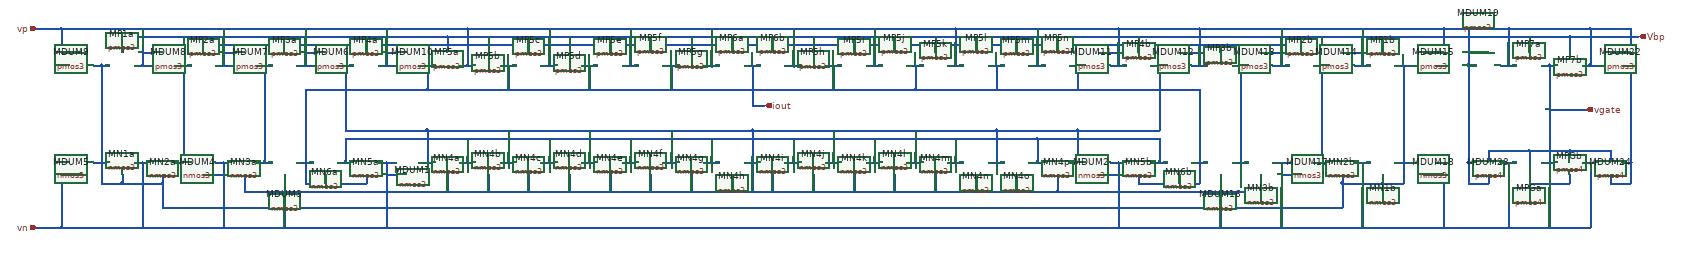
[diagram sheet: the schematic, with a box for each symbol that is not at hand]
v {xschem version=2.9.9 file_version=1.2 }
G {}
K {}
V {}
S {}
E {}
N 4100 -430 4250 -430 { lab=vp}
N 4360 -230 4450 -230 { lab=igate}
N 1680 -340 1700 -340 { lab=vp}
N 900 -340 920 -340 { lab=vp}
N 1080 -340 1120 -340 { lab=vp}
N 1100 -430 1100 -340 { lab=vp}
N 1480 -340 1520 -340 { lab=vp}
N 1280 -340 1320 -340 { lab=vp}
N 980 -340 1020 -340 { lab=Vbp}
N 1380 -340 1420 -340 { lab=#net1}
N 1580 -340 1620 -340 { lab=#net2}
N 950 -410 1050 -410 { lab=Vbp}
N 1650 -410 1650 -370 { lab=Vbp}
N 1650 -410 1830 -410 { lab=Vbp}
N 870 -430 910 -430 { lab=vp}
N 910 -430 1680 -430 { lab=vp}
N 1680 -430 1700 -430 { lab=vp}
N 1100 -100 1120 -100 { lab=vn}
N 1830 -410 2920 -410 { lab=Vbp}
N 1700 -340 1720 -340 { lab=vp}
N 1700 -430 2900 -430 { lab=vp}
N 1780 -340 1820 -340 { lab=#net2}
N 1880 -340 1920 -340 { lab=vp}
N 1980 -340 2020 -340 { lab=#net2}
N 2080 -340 2120 -340 { lab=vp}
N 2180 -340 2220 -340 { lab=#net2}
N 2280 -340 2320 -340 { lab=vp}
N 2380 -340 2420 -340 { lab=iout}
N 2480 -340 2520 -340 { lab=vp}
N 2580 -340 2620 -340 { lab=#net2}
N 2680 -340 2720 -340 { lab=vp}
N 2780 -340 2820 -340 { lab=#net2}
N 1850 -410 1850 -370 { lab=Vbp}
N 1750 -410 1750 -370 { lab=Vbp}
N 2050 -410 2050 -370 { lab=Vbp}
N 1950 -410 1950 -370 { lab=Vbp}
N 2250 -410 2250 -370 { lab=Vbp}
N 2150 -410 2150 -370 { lab=Vbp}
N 2450 -410 2450 -370 { lab=Vbp}
N 2350 -410 2350 -370 { lab=Vbp}
N 2650 -410 2650 -370 { lab=Vbp}
N 2550 -410 2550 -370 { lab=Vbp}
N 2850 -410 2850 -370 { lab=Vbp}
N 2750 -410 2750 -370 { lab=Vbp}
N 1600 -280 2800 -280 { lab=#net2}
N 1300 60 1500 60 { lab=vn}
N 1480 -100 1500 -100 { lab=vn}
N 3300 -430 3500 -430 { lab=vp}
N 3320 -410 3560 -410 { lab=Vbp}
N 3350 -410 3350 -370 { lab=Vbp}
N 2880 -340 2920 -340 { lab=vp}
N 2980 -340 3020 -340 { lab=#net2}
N 2900 -430 3300 -430 { lab=vp}
N 2920 -410 3320 -410 { lab=Vbp}
N 2950 -410 2950 -370 { lab=Vbp}
N 3050 -410 3050 -370 { lab=Vbp}
N 3150 -410 3150 -370 { lab=Vbp}
N 1500 -100 1520 -100 { lab=vn}
N 1500 -70 1550 -70 { lab=vn}
N 1580 -100 1620 -100 { lab=#net1}
N 1500 60 3300 60 { lab=vn}
N 3280 -100 3300 -100 { lab=vn}
N 3250 -70 3300 -70 { lab=vn}
N 3180 -100 3220 -100 { lab=#net1}
N 1680 -100 1720 -100 { lab=#net3}
N 1780 -100 1820 -100 { lab=#net1}
N 1880 -100 1920 -100 { lab=#net3}
N 1980 -100 2020 -100 { lab=#net1}
N 2080 -100 2120 -100 { lab=#net3}
N 2180 -100 2220 -100 { lab=#net1}
N 2280 -100 2320 -100 { lab=#net3}
N 2380 -100 2410 -100 { lab=#net1}
N 2410 -100 2420 -100 { lab=#net1}
N 2480 -100 2520 -100 { lab=#net3}
N 2580 -100 2620 -100 { lab=#net1}
N 2690 -100 2720 -100 { lab=#net3}
N 2680 -100 2690 -100 { lab=#net3}
N 2780 -100 2820 -100 { lab=#net1}
N 2880 -100 2920 -100 { lab=#net3}
N 2980 -100 3020 -100 { lab=#net1}
N 3080 -100 3120 -100 { lab=#net3}
N 1530 -30 2470 -30 { lab=#net1}
N 2470 -30 3150 -30 { lab=#net1}
N 1400 -160 3100 -160 { lab=#net3}
N 2400 -170 2400 -100 { lab=#net1}
N 2400 -180 2400 -170 { lab=#net1}
N 2400 -180 3000 -180 { lab=#net1}
N 2600 -180 2600 -100 { lab=#net1}
N 2800 -180 2800 -100 { lab=#net1}
N 3000 -120 3000 -100 { lab=#net1}
N 3000 -180 3200 -180 { lab=#net1}
N 3200 -180 3200 -100 { lab=#net1}
N 1600 -180 2400 -180 { lab=#net1}
N 1600 -180 1600 -100 { lab=#net1}
N 1800 -180 1800 -100 { lab=#net1}
N 2000 -180 2000 -100 { lab=#net1}
N 2200 -180 2200 -100 { lab=#net1}
N 3100 -150 3100 -100 { lab=#net3}
N 3100 -160 3100 -150 { lab=#net3}
N 2900 -160 2900 -100 { lab=#net3}
N 2700 -160 2700 -100 { lab=#net3}
N 2500 -160 2500 -100 { lab=#net3}
N 2300 -160 2300 -100 { lab=#net3}
N 2100 -160 2100 -100 { lab=#net3}
N 1900 -160 1900 -100 { lab=#net3}
N 1700 -150 1700 -100 { lab=#net3}
N 1700 -160 1700 -150 { lab=#net3}
N 1400 -160 1400 -100 { lab=#net3}
N 1380 -100 1420 -100 { lab=#net3}
N 1320 -50 1450 -50 { lab=#net2}
N 3000 -180 3000 -120 { lab=#net1}
N 3150 -70 3150 -50 { lab=#net1}
N 1310 -100 1320 -100 { lab=#net2}
N 1310 -50 1320 -50 { lab=#net2}
N 1280 -100 1290 -100 { lab=#net2}
N 1180 -100 1220 -100 { lab=#net4}
N 1150 -70 1150 -50 { lab=#net1}
N 1100 60 1290 60 { lab=vn}
N 1290 60 1300 60 { lab=vn}
N 1080 -100 1100 -100 { lab=vn}
N 1050 -70 1100 -70 { lab=vn}
N 900 60 1100 60 { lab=vn}
N 880 -100 900 -100 { lab=vn}
N 900 -100 920 -100 { lab=vn}
N 780 -100 820 -100 { lab=#net5}
N 700 -100 720 -100 { lab=vn}
N 700 60 900 60 { lab=vn}
N 700 -70 750 -70 { lab=vn}
N 980 -100 1020 -100 { lab=Vbp}
N 850 -70 850 -50 { lab=#net5}
N 850 -50 950 -50 { lab=#net5}
N 950 -70 950 -50 { lab=#net5}
N 800 -50 850 -50 { lab=#net5}
N 800 -100 800 -50 { lab=#net5}
N 1450 -410 1450 -370 { lab=Vbp}
N 1300 -370 1350 -370 { lab=vp}
N 2400 -100 2400 -50 { lab=#net1}
N 1300 -280 1300 -190 { lab=#net2}
N 1310 -280 1600 -280 { lab=#net2}
N 1200 -340 1220 -340 { lab=#net4}
N 1100 -370 1150 -370 { lab=vp}
N 1180 -340 1200 -340 { lab=#net4}
N 800 -340 810 -340 { lab=#net5}
N 1050 -390 1050 -370 { lab=#net4}
N 870 -410 950 -410 { lab=Vbp}
N 850 -410 870 -410 { lab=Vbp}
N 850 -410 850 -370 { lab=Vbp}
N 810 -340 820 -340 { lab=#net5}
N 880 -340 900 -340 { lab=vp}
N 700 -430 870 -430 { lab=vp}
N 640 -430 700 -430 { lab=vp}
N 780 -340 800 -340 { lab=#net5}
N 700 -340 720 -340 { lab=vp}
N 700 -430 700 -340 { lab=vp}
N 700 -370 750 -370 { lab=vp}
N 1350 -70 1350 -50 { lab=#net2}
N 1450 -70 1450 -50 { lab=#net2}
N 1150 -50 1150 -30 { lab=#net1}
N 3150 -50 3150 -30 { lab=#net1}
N 3050 -70 3050 -50 { lab=#net1}
N 3050 -50 3050 -30 { lab=#net1}
N 2950 -70 2950 -50 { lab=#net1}
N 2950 -50 2950 -30 { lab=#net1}
N 2850 -70 2850 -50 { lab=#net1}
N 2850 -50 2850 -30 { lab=#net1}
N 2750 -70 2750 -50 { lab=#net1}
N 2750 -50 2750 -30 { lab=#net1}
N 2650 -70 2650 -50 { lab=#net1}
N 2650 -50 2650 -30 { lab=#net1}
N 2550 -70 2550 -50 { lab=#net1}
N 2550 -50 2550 -30 { lab=#net1}
N 2450 -70 2450 -50 { lab=#net1}
N 2450 -50 2450 -30 { lab=#net1}
N 2350 -70 2350 -50 { lab=#net1}
N 2350 -50 2350 -30 { lab=#net1}
N 2250 -70 2250 -50 { lab=#net1}
N 2250 -50 2250 -30 { lab=#net1}
N 2150 -70 2150 -50 { lab=#net1}
N 2150 -50 2150 -30 { lab=#net1}
N 2050 -70 2050 -50 { lab=#net1}
N 2050 -50 2050 -30 { lab=#net1}
N 1950 -70 1950 -50 { lab=#net1}
N 1950 -50 1950 -30 { lab=#net1}
N 1850 -70 1850 -50 { lab=#net1}
N 1850 -50 1850 -30 { lab=#net1}
N 1750 -70 1750 -50 { lab=#net1}
N 1750 -50 1750 -30 { lab=#net1}
N 1650 -70 1650 -50 { lab=#net1}
N 1650 -50 1650 -30 { lab=#net1}
N 1150 -30 1530 -30 { lab=#net1}
N 2800 -280 3000 -280 { lab=#net2}
N 1500 -180 1600 -180 { lab=#net1}
N 900 -430 900 -340 { lab=vp}
N 800 -340 800 -240 { lab=#net5}
N 800 -240 800 -100 { lab=#net5}
N 900 -370 950 -370 { lab=vp}
N 1000 -340 1000 -240 { lab=Vbp}
N 1000 -240 1000 -100 { lab=Vbp}
N 1200 -340 1200 -300 { lab=#net4}
N 1200 -300 1200 -100 { lab=#net4}
N 1250 -390 1250 -370 { lab=#net4}
N 1200 -390 1200 -340 { lab=#net4}
N 1050 -390 1250 -390 { lab=#net4}
N 2300 -430 2300 -340 { lab=vp}
N 2100 -430 2100 -340 { lab=vp}
N 1900 -430 1900 -340 { lab=vp}
N 1700 -430 1700 -340 { lab=vp}
N 1050 -410 1650 -410 { lab=Vbp}
N 2400 -50 2400 -30 { lab=#net1}
N 1600 -340 1600 -280 { lab=#net2}
N 1800 -340 1800 -280 { lab=#net2}
N 2000 -340 2000 -280 { lab=#net2}
N 2200 -340 2200 -280 { lab=#net2}
N 3080 -340 3120 -340 { lab=vp}
N 3180 -340 3220 -340 { lab=#net2}
N 3280 -340 3320 -340 { lab=vp}
N 3200 -340 3200 -280 { lab=#net2}
N 2500 -430 2500 -340 { lab=vp}
N 3000 -280 3200 -280 { lab=#net2}
N 2400 -340 2400 -240 { lab=iout}
N 2400 -240 2430 -240 { lab=iout}
N 640 60 700 60 { lab=vn}
N 2700 -430 2700 -340 { lab=vp}
N 2900 -430 2900 -340 { lab=vp}
N 3100 -430 3100 -340 { lab=vp}
N 3000 -340 3000 -280 { lab=#net2}
N 2800 -340 2800 -280 { lab=#net2}
N 2600 -340 2600 -280 { lab=#net2}
N 3380 -340 3420 -340 { lab=#net1}
N 3500 -430 3500 -340 { lab=vp}
N 3450 -370 3500 -370 { lab=vp}
N 3200 -180 3300 -180 { lab=#net1}
N 3500 -430 4000 -430 { lab=vp}
N 4000 -430 4100 -430 { lab=vp}
N 4100 -430 4100 -340 { lab=vp}
N 4080 -340 4100 -340 { lab=vp}
N 4050 -370 4100 -370 { lab=vp}
N 3980 -340 4020 -340 { lab=#net5}
N 3880 -340 3920 -340 { lab=vp}
N 3780 -340 3820 -340 { lab=Vbp}
N 3680 -340 3720 -340 { lab=vp}
N 3580 -340 3620 -340 { lab=#net4}
N 3480 -340 3520 -340 { lab=vp}
N 3560 -410 4140 -410 { lab=Vbp}
N 3300 60 4100 60 { lab=vn}
N 4100 -100 4100 -10 { lab=vn}
N 4080 -100 4100 -100 { lab=vn}
N 4050 -70 4100 -70 { lab=vn}
N 3980 -100 4020 -100 { lab=#net5}
N 3880 -100 3920 -100 { lab=vn}
N 3780 -100 3820 -100 { lab=Vbp}
N 3680 -100 3720 -100 { lab=vn}
N 3580 -100 3620 -100 { lab=#net4}
N 3480 -100 3520 -100 { lab=#net2}
N 3380 -100 3420 -100 { lab=#net3}
N 3300 -100 3320 -100 { lab=vn}
N 1290 -100 1310 -100 { lab=#net2}
N 1300 -280 1310 -280 { lab=#net2}
N 1300 -190 1300 -100 { lab=#net2}
N 1300 -100 1300 -50 { lab=#net2}
N 1300 -50 1310 -50 { lab=#net2}
N 3100 -160 3400 -160 { lab=#net3}
N 3400 -160 3400 -100 { lab=#net3}
N 3500 -200 3500 -100 { lab=#net2}
N 3500 -280 3500 -200 { lab=#net2}
N 3200 -280 3500 -280 { lab=#net2}
N 3500 -100 3500 -50 { lab=#net2}
N 3350 -50 3500 -50 { lab=#net2}
N 3350 -70 3350 -50 { lab=#net2}
N 3450 -70 3450 -50 { lab=#net2}
N 3700 -70 3750 -70 { lab=vn}
N 3900 -100 3900 -10 { lab=vn}
N 3950 -70 3950 -50 { lab=#net5}
N 3850 -70 3850 -50 { lab=#net5}
N 3850 -50 3950 -50 { lab=#net5}
N 3950 -50 4000 -50 { lab=#net5}
N 4000 -100 4000 -50 { lab=#net5}
N 4000 -150 4000 -100 { lab=#net5}
N 3800 -160 3800 -100 { lab=Vbp}
N 3600 -160 3600 -100 { lab=#net4}
N 3750 -390 3750 -370 { lab=#net4}
N 3550 -390 3550 -370 { lab=#net4}
N 3600 -390 3600 -340 { lab=#net4}
N 3600 -300 3600 -160 { lab=#net4}
N 3600 -340 3600 -300 { lab=#net4}
N 3150 -30 3650 -30 { lab=#net1}
N 3650 -70 3650 -30 { lab=#net1}
N 3700 -430 3700 -340 { lab=vp}
N 3650 -370 3700 -370 { lab=vp}
N 3800 -340 3800 -240 { lab=Vbp}
N 3800 -240 3800 -160 { lab=Vbp}
N 3850 -370 3900 -370 { lab=vp}
N 3900 -430 3900 -340 { lab=vp}
N 4000 -340 4000 -240 { lab=#net5}
N 4000 -240 4000 -150 { lab=#net5}
N 4100 -10 4100 60 { lab=vn}
N 3900 -10 3900 60 { lab=vn}
N 3700 -100 3700 60 { lab=vn}
N 3550 -70 3550 60 { lab=vn}
N 3300 -100 3300 60 { lab=vn}
N 1500 -100 1500 60 { lab=vn}
N 1250 -70 1250 60 { lab=vn}
N 1100 -100 1100 60 { lab=vn}
N 900 -100 900 60 { lab=vn}
N 700 -100 700 60 { lab=vn}
N 950 -50 950 10 { lab=#net5}
N 950 10 3850 10 { lab=#net5}
N 3850 -50 3850 10 { lab=#net5}
N 3950 -410 3950 -370 { lab=Vbp}
N 1000 -410 1000 -340 { lab=Vbp}
N 3800 -410 3800 -340 { lab=Vbp}
N 1250 -390 3750 -390 { lab=#net4}
N 1300 -430 1300 -340 { lab=vp}
N 1400 -340 1400 -180 { lab=#net1}
N 1400 -180 1500 -180 { lab=#net1}
N 1500 -430 1500 -340 { lab=vp}
N 1500 -370 1550 -370 { lab=vp}
N 3400 -340 3400 -180 { lab=#net1}
N 3300 -180 3400 -180 { lab=#net1}
N 3300 -430 3300 -340 { lab=vp}
N 3250 -370 3300 -370 { lab=vp}
N 4240 -100 4280 -100 { lab=vn}
N 4160 -100 4180 -100 { lab=vp}
N 4310 -130 4310 -100 { lab=igate}
N 4310 -130 4410 -130 { lab=igate}
N 4410 -130 4410 -100 { lab=igate}
N 4340 -100 4380 -100 { lab=igate}
N 4360 -130 4360 -100 { lab=igate}
N 4360 -340 4360 -130 { lab=igate}
N 4340 -340 4360 -340 { lab=igate}
N 4360 -340 4380 -340 { lab=igate}
N 4240 -340 4280 -340 { lab=vp}
N 4260 -430 4260 -350 { lab=vp}
N 4260 -350 4260 -340 { lab=vp}
N 4250 -430 4260 -430 { lab=vp}
N 4440 -100 4480 -100 { lab=vn}
N 4260 -100 4260 60 { lab=vn}
N 4100 60 4260 60 { lab=vn}
N 4460 -100 4460 60 { lab=vn}
N 4260 60 4460 60 { lab=vn}
N 4210 -130 4210 -100 { lab=igate}
N 4210 -130 4310 -130 { lab=igate}
N 4510 -130 4510 -100 { lab=igate}
N 4410 -130 4510 -130 { lab=igate}
N 4140 -410 4410 -410 { lab=Vbp}
N 4310 -410 4310 -370 { lab=Vbp}
N 4410 -410 4410 -370 { lab=Vbp}
N 4260 -430 4460 -430 { lab=vp}
N 4460 -430 4460 -340 { lab=vp}
N 4440 -340 4460 -340 { lab=vp}
N 4460 -340 4480 -340 { lab=vp}
N 4160 -430 4160 -340 { lab=vp}
N 4460 -430 4530 -430 { lab=vp}
N 4530 -430 4540 -430 { lab=vp}
N 4510 -370 4540 -370 { lab=vp}
N 4410 -410 4580 -410 { lab=Vbp}
N 4540 -340 4560 -340 { lab=vp}
N 4560 -430 4560 -340 { lab=vp}
N 4540 -430 4560 -430 { lab=vp}
N 4540 -370 4560 -370 { lab=vp}
N 4160 -340 4180 -340 { lab=vp}
N 4160 -370 4210 -370 { lab=vp}
N 4160 -340 4160 -100 { lab=vp}
N 4540 -100 4560 -100 { lab=#net6}
N 4560 -340 4560 -110 { lab=vp}
N 4310 -70 4310 -50 {}
N 4310 -50 4410 -50 {}
N 4410 -70 4410 -50 {}
N 4360 -50 4360 60 {}
N 4210 -70 4210 -50 {}
N 4160 -50 4210 -50 {}
N 4160 -100 4160 -50 {}
N 4510 -70 4510 -50 {}
N 4510 -50 4560 -50 {}
N 4560 -100 4560 -50 {}
N 4560 -110 4560 -100 {}
C {devices/iopin.sym} 640 -430 2 0 {name=p1 lab=vp}
C {devices/iopin.sym} 640 60 2 0 {name=p2 lab=vn}
C {devices/opin.sym} 2430 -240 0 0 {name=p3 lab=iout}
C {devices/opin.sym} 4580 -410 0 0 {name=p4 lab=Vbp}
C {devices/opin.sym} 4450 -230 0 0 {name=p5 lab=vgate}
C {madvlsi/pmos3.sym} 850 -340 1 0 {name=MP1a
L=2
W=5
body=VDD
nf=1
mult=1
ad="'int((nf+1)/2) * W/nf * 0.29'" 
pd="'2*int((nf+1)/2) * (W/nf + 0.29)'"
as="'int((nf+2)/2) * W/nf * 0.29'" 
ps="'2*int((nf+2)/2) * (W/nf + 0.29)'"
nrd="'0.29 / W'" nrs="'0.29 / W'"
sa=0 sb=0 sd=0
model=pfet_01v8
spiceprefix=X
}
C {madvlsi/pmos3.sym} 3950 -340 1 0 {name=MP1b
L=2
W=5
body=VDD
nf=1
mult=1
ad="'int((nf+1)/2) * W/nf * 0.29'" 
pd="'2*int((nf+1)/2) * (W/nf + 0.29)'"
as="'int((nf+2)/2) * W/nf * 0.29'" 
ps="'2*int((nf+2)/2) * (W/nf + 0.29)'"
nrd="'0.29 / W'" nrs="'0.29 / W'"
sa=0 sb=0 sd=0
model=pfet_01v8
spiceprefix=X
}
C {madvlsi/pmos3.sym} 1050 -340 1 0 {name=MP2a
L=2
W=5
body=VDD
nf=1
mult=1
ad="'int((nf+1)/2) * W/nf * 0.29'" 
pd="'2*int((nf+1)/2) * (W/nf + 0.29)'"
as="'int((nf+2)/2) * W/nf * 0.29'" 
ps="'2*int((nf+2)/2) * (W/nf + 0.29)'"
nrd="'0.29 / W'" nrs="'0.29 / W'"
sa=0 sb=0 sd=0
model=pfet_01v8
spiceprefix=X
}
C {madvlsi/pmos3.sym} 3750 -340 1 0 {name=MP2b
L=2
W=5
body=VDD
nf=1
mult=1
ad="'int((nf+1)/2) * W/nf * 0.29'" 
pd="'2*int((nf+1)/2) * (W/nf + 0.29)'"
as="'int((nf+2)/2) * W/nf * 0.29'" 
ps="'2*int((nf+2)/2) * (W/nf + 0.29)'"
nrd="'0.29 / W'" nrs="'0.29 / W'"
sa=0 sb=0 sd=0
model=pfet_01v8
spiceprefix=X
}
C {madvlsi/pmos3.sym} 1250 -340 1 0 {name=MP3a
L=2
W=5
body=VDD
nf=1
mult=1
ad="'int((nf+1)/2) * W/nf * 0.29'" 
pd="'2*int((nf+1)/2) * (W/nf + 0.29)'"
as="'int((nf+2)/2) * W/nf * 0.29'" 
ps="'2*int((nf+2)/2) * (W/nf + 0.29)'"
nrd="'0.29 / W'" nrs="'0.29 / W'"
sa=0 sb=0 sd=0
model=pfet_01v8
spiceprefix=X
}
C {madvlsi/pmos3.sym} 3550 -340 1 0 {name=MP3b
L=2
W=5
body=VDD
nf=1
mult=1
ad="'int((nf+1)/2) * W/nf * 0.29'" 
pd="'2*int((nf+1)/2) * (W/nf + 0.29)'"
as="'int((nf+2)/2) * W/nf * 0.29'" 
ps="'2*int((nf+2)/2) * (W/nf + 0.29)'"
nrd="'0.29 / W'" nrs="'0.29 / W'"
sa=0 sb=0 sd=0
model=pfet_01v8
spiceprefix=X
}
C {madvlsi/pmos3.sym} 1450 -340 1 0 {name=MP4a
L=2
W=5
body=VDD
nf=1
mult=1
ad="'int((nf+1)/2) * W/nf * 0.29'" 
pd="'2*int((nf+1)/2) * (W/nf + 0.29)'"
as="'int((nf+2)/2) * W/nf * 0.29'" 
ps="'2*int((nf+2)/2) * (W/nf + 0.29)'"
nrd="'0.29 / W'" nrs="'0.29 / W'"
sa=0 sb=0 sd=0
model=pfet_01v8
spiceprefix=X
}
C {madvlsi/pmos3.sym} 3350 -340 1 0 {name=MP4b
L=2
W=5
body=VDD
nf=1
mult=1
ad="'int((nf+1)/2) * W/nf * 0.29'" 
pd="'2*int((nf+1)/2) * (W/nf + 0.29)'"
as="'int((nf+2)/2) * W/nf * 0.29'" 
ps="'2*int((nf+2)/2) * (W/nf + 0.29)'"
nrd="'0.29 / W'" nrs="'0.29 / W'"
sa=0 sb=0 sd=0
model=pfet_01v8
spiceprefix=X
}
C {madvlsi/nmos3.sym} 850 -100 3 0 {name=MN1a
L=2
W=5
body=GND
nf=1
mult=1
ad="'int((nf+1)/2) * W/nf * 0.29'" 
pd="'2*int((nf+1)/2) * (W/nf + 0.29)'"
as="'int((nf+2)/2) * W/nf * 0.29'" 
ps="'2*int((nf+2)/2) * (W/nf + 0.29)'"
nrd="'0.29 / W'" nrs="'0.29 / W'"
sa=0 sb=0 sd=0
model=nfet_01v8
spiceprefix=X
}
C {madvlsi/nmos3.sym} 3950 -100 3 0 {name=MN1b
L=2
W=5
body=GND
nf=1
mult=1
ad="'int((nf+1)/2) * W/nf * 0.29'" 
pd="'2*int((nf+1)/2) * (W/nf + 0.29)'"
as="'int((nf+2)/2) * W/nf * 0.29'" 
ps="'2*int((nf+2)/2) * (W/nf + 0.29)'"
nrd="'0.29 / W'" nrs="'0.29 / W'"
sa=0 sb=0 sd=0
model=nfet_01v8
spiceprefix=X
}
C {madvlsi/nmos3.sym} 950 -100 3 0 {name=MN2a
L=2
W=5
body=GND
nf=1
mult=1
ad="'int((nf+1)/2) * W/nf * 0.29'" 
pd="'2*int((nf+1)/2) * (W/nf + 0.29)'"
as="'int((nf+2)/2) * W/nf * 0.29'" 
ps="'2*int((nf+2)/2) * (W/nf + 0.29)'"
nrd="'0.29 / W'" nrs="'0.29 / W'"
sa=0 sb=0 sd=0
model=nfet_01v8
spiceprefix=X
}
C {madvlsi/nmos3.sym} 3850 -100 3 0 {name=MN2b
L=2
W=5
body=GND
nf=1
mult=1
ad="'int((nf+1)/2) * W/nf * 0.29'" 
pd="'2*int((nf+1)/2) * (W/nf + 0.29)'"
as="'int((nf+2)/2) * W/nf * 0.29'" 
ps="'2*int((nf+2)/2) * (W/nf + 0.29)'"
nrd="'0.29 / W'" nrs="'0.29 / W'"
sa=0 sb=0 sd=0
model=nfet_01v8
spiceprefix=X
}
C {madvlsi/nmos3.sym} 1150 -100 3 0 {name=MN3a
L=2
W=5
body=GND
nf=1
mult=1
ad="'int((nf+1)/2) * W/nf * 0.29'" 
pd="'2*int((nf+1)/2) * (W/nf + 0.29)'"
as="'int((nf+2)/2) * W/nf * 0.29'" 
ps="'2*int((nf+2)/2) * (W/nf + 0.29)'"
nrd="'0.29 / W'" nrs="'0.29 / W'"
sa=0 sb=0 sd=0
model=nfet_01v8
spiceprefix=X
}
C {madvlsi/nmos3.sym} 3650 -100 3 0 {name=MN3b
L=2
W=5
body=GND
nf=1
mult=1
ad="'int((nf+1)/2) * W/nf * 0.29'" 
pd="'2*int((nf+1)/2) * (W/nf + 0.29)'"
as="'int((nf+2)/2) * W/nf * 0.29'" 
ps="'2*int((nf+2)/2) * (W/nf + 0.29)'"
nrd="'0.29 / W'" nrs="'0.29 / W'"
sa=0 sb=0 sd=0
model=nfet_01v8
spiceprefix=X
}
C {madvlsi/nmos3.sym} 1450 -100 3 0 {name=MN5a
L=2
W=5
body=GND
nf=1
mult=1
ad="'int((nf+1)/2) * W/nf * 0.29'" 
pd="'2*int((nf+1)/2) * (W/nf + 0.29)'"
as="'int((nf+2)/2) * W/nf * 0.29'" 
ps="'2*int((nf+2)/2) * (W/nf + 0.29)'"
nrd="'0.29 / W'" nrs="'0.29 / W'"
sa=0 sb=0 sd=0
model=nfet_01v8
spiceprefix=X
}
C {madvlsi/nmos3.sym} 3350 -100 3 0 {name=MN5b
L=2
W=5
body=GND
nf=1
mult=1
ad="'int((nf+1)/2) * W/nf * 0.29'" 
pd="'2*int((nf+1)/2) * (W/nf + 0.29)'"
as="'int((nf+2)/2) * W/nf * 0.29'" 
ps="'2*int((nf+2)/2) * (W/nf + 0.29)'"
nrd="'0.29 / W'" nrs="'0.29 / W'"
sa=0 sb=0 sd=0
model=nfet_01v8
spiceprefix=X
}
C {madvlsi/nmos3.sym} 1350 -100 3 0 {name=MN6a
L=2
W=5
body=GND
nf=1
mult=1
ad="'int((nf+1)/2) * W/nf * 0.29'" 
pd="'2*int((nf+1)/2) * (W/nf + 0.29)'"
as="'int((nf+2)/2) * W/nf * 0.29'" 
ps="'2*int((nf+2)/2) * (W/nf + 0.29)'"
nrd="'0.29 / W'" nrs="'0.29 / W'"
sa=0 sb=0 sd=0
model=nfet_01v8
spiceprefix=X
}
C {madvlsi/nmos3.sym} 3450 -100 3 0 {name=MN6b
L=2
W=5
body=GND
nf=1
mult=1
ad="'int((nf+1)/2) * W/nf * 0.29'" 
pd="'2*int((nf+1)/2) * (W/nf + 0.29)'"
as="'int((nf+2)/2) * W/nf * 0.29'" 
ps="'2*int((nf+2)/2) * (W/nf + 0.29)'"
nrd="'0.29 / W'" nrs="'0.29 / W'"
sa=0 sb=0 sd=0
model=nfet_01v8
spiceprefix=X
}
C {madvlsi/pmos3.sym} 2250 -340 1 0 {name=MP5g
L=2
W=5
body=VDD
nf=1
mult=1
ad="'int((nf+1)/2) * W/nf * 0.29'" 
pd="'2*int((nf+1)/2) * (W/nf + 0.29)'"
as="'int((nf+2)/2) * W/nf * 0.29'" 
ps="'2*int((nf+2)/2) * (W/nf + 0.29)'"
nrd="'0.29 / W'" nrs="'0.29 / W'"
sa=0 sb=0 sd=0
model=pfet_01v8
spiceprefix=X
}
C {madvlsi/pmos3.sym} 2550 -340 1 0 {name=MP5h
L=2
W=5
body=VDD
nf=1
mult=1
ad="'int((nf+1)/2) * W/nf * 0.29'" 
pd="'2*int((nf+1)/2) * (W/nf + 0.29)'"
as="'int((nf+2)/2) * W/nf * 0.29'" 
ps="'2*int((nf+2)/2) * (W/nf + 0.29)'"
nrd="'0.29 / W'" nrs="'0.29 / W'"
sa=0 sb=0 sd=0
model=pfet_01v8
spiceprefix=X
}
C {madvlsi/pmos3.sym} 1650 -340 1 0 {name=MP5a
L=2
W=5
body=VDD
nf=1
mult=1
ad="'int((nf+1)/2) * W/nf * 0.29'" 
pd="'2*int((nf+1)/2) * (W/nf + 0.29)'"
as="'int((nf+2)/2) * W/nf * 0.29'" 
ps="'2*int((nf+2)/2) * (W/nf + 0.29)'"
nrd="'0.29 / W'" nrs="'0.29 / W'"
sa=0 sb=0 sd=0
model=pfet_01v8
spiceprefix=X
}
C {madvlsi/pmos3.sym} 1750 -340 1 0 {name=MP5b
L=2
W=5
body=VDD
nf=1
mult=1
ad="'int((nf+1)/2) * W/nf * 0.29'" 
pd="'2*int((nf+1)/2) * (W/nf + 0.29)'"
as="'int((nf+2)/2) * W/nf * 0.29'" 
ps="'2*int((nf+2)/2) * (W/nf + 0.29)'"
nrd="'0.29 / W'" nrs="'0.29 / W'"
sa=0 sb=0 sd=0
model=pfet_01v8
spiceprefix=X
}
C {madvlsi/pmos3.sym} 1850 -340 1 0 {name=MP5c
L=2
W=5
body=VDD
nf=1
mult=1
ad="'int((nf+1)/2) * W/nf * 0.29'" 
pd="'2*int((nf+1)/2) * (W/nf + 0.29)'"
as="'int((nf+2)/2) * W/nf * 0.29'" 
ps="'2*int((nf+2)/2) * (W/nf + 0.29)'"
nrd="'0.29 / W'" nrs="'0.29 / W'"
sa=0 sb=0 sd=0
model=pfet_01v8
spiceprefix=X
}
C {madvlsi/pmos3.sym} 1950 -340 1 0 {name=MP5d
L=2
W=5
body=VDD
nf=1
mult=1
ad="'int((nf+1)/2) * W/nf * 0.29'" 
pd="'2*int((nf+1)/2) * (W/nf + 0.29)'"
as="'int((nf+2)/2) * W/nf * 0.29'" 
ps="'2*int((nf+2)/2) * (W/nf + 0.29)'"
nrd="'0.29 / W'" nrs="'0.29 / W'"
sa=0 sb=0 sd=0
model=pfet_01v8
spiceprefix=X
}
C {madvlsi/pmos3.sym} 2050 -340 1 0 {name=MP5e
L=2
W=5
body=VDD
nf=1
mult=1
ad="'int((nf+1)/2) * W/nf * 0.29'" 
pd="'2*int((nf+1)/2) * (W/nf + 0.29)'"
as="'int((nf+2)/2) * W/nf * 0.29'" 
ps="'2*int((nf+2)/2) * (W/nf + 0.29)'"
nrd="'0.29 / W'" nrs="'0.29 / W'"
sa=0 sb=0 sd=0
model=pfet_01v8
spiceprefix=X
}
C {madvlsi/pmos3.sym} 2150 -340 1 0 {name=MP5f
L=2
W=5
body=VDD
nf=1
mult=1
ad="'int((nf+1)/2) * W/nf * 0.29'" 
pd="'2*int((nf+1)/2) * (W/nf + 0.29)'"
as="'int((nf+2)/2) * W/nf * 0.29'" 
ps="'2*int((nf+2)/2) * (W/nf + 0.29)'"
nrd="'0.29 / W'" nrs="'0.29 / W'"
sa=0 sb=0 sd=0
model=pfet_01v8
spiceprefix=X
}
C {madvlsi/pmos3.sym} 2650 -340 1 0 {name=MP5i
L=2
W=5
body=VDD
nf=1
mult=1
ad="'int((nf+1)/2) * W/nf * 0.29'" 
pd="'2*int((nf+1)/2) * (W/nf + 0.29)'"
as="'int((nf+2)/2) * W/nf * 0.29'" 
ps="'2*int((nf+2)/2) * (W/nf + 0.29)'"
nrd="'0.29 / W'" nrs="'0.29 / W'"
sa=0 sb=0 sd=0
model=pfet_01v8
spiceprefix=X
}
C {madvlsi/pmos3.sym} 2750 -340 1 0 {name=MP5j
L=2
W=5
body=VDD
nf=1
mult=1
ad="'int((nf+1)/2) * W/nf * 0.29'" 
pd="'2*int((nf+1)/2) * (W/nf + 0.29)'"
as="'int((nf+2)/2) * W/nf * 0.29'" 
ps="'2*int((nf+2)/2) * (W/nf + 0.29)'"
nrd="'0.29 / W'" nrs="'0.29 / W'"
sa=0 sb=0 sd=0
model=pfet_01v8
spiceprefix=X
}
C {madvlsi/pmos3.sym} 2850 -340 1 0 {name=MP5k
L=2
W=5
body=VDD
nf=1
mult=1
ad="'int((nf+1)/2) * W/nf * 0.29'" 
pd="'2*int((nf+1)/2) * (W/nf + 0.29)'"
as="'int((nf+2)/2) * W/nf * 0.29'" 
ps="'2*int((nf+2)/2) * (W/nf + 0.29)'"
nrd="'0.29 / W'" nrs="'0.29 / W'"
sa=0 sb=0 sd=0
model=pfet_01v8
spiceprefix=X
}
C {madvlsi/pmos3.sym} 2950 -340 1 0 {name=MP5l
L=2
W=5
body=VDD
nf=1
mult=1
ad="'int((nf+1)/2) * W/nf * 0.29'" 
pd="'2*int((nf+1)/2) * (W/nf + 0.29)'"
as="'int((nf+2)/2) * W/nf * 0.29'" 
ps="'2*int((nf+2)/2) * (W/nf + 0.29)'"
nrd="'0.29 / W'" nrs="'0.29 / W'"
sa=0 sb=0 sd=0
model=pfet_01v8
spiceprefix=X
}
C {madvlsi/pmos3.sym} 3050 -340 1 0 {name=MP5m
L=2
W=5
body=VDD
nf=1
mult=1
ad="'int((nf+1)/2) * W/nf * 0.29'" 
pd="'2*int((nf+1)/2) * (W/nf + 0.29)'"
as="'int((nf+2)/2) * W/nf * 0.29'" 
ps="'2*int((nf+2)/2) * (W/nf + 0.29)'"
nrd="'0.29 / W'" nrs="'0.29 / W'"
sa=0 sb=0 sd=0
model=pfet_01v8
spiceprefix=X
}
C {madvlsi/pmos3.sym} 3150 -340 1 0 {name=MP5n
L=2
W=5
body=VDD
nf=1
mult=1
ad="'int((nf+1)/2) * W/nf * 0.29'" 
pd="'2*int((nf+1)/2) * (W/nf + 0.29)'"
as="'int((nf+2)/2) * W/nf * 0.29'" 
ps="'2*int((nf+2)/2) * (W/nf + 0.29)'"
nrd="'0.29 / W'" nrs="'0.29 / W'"
sa=0 sb=0 sd=0
model=pfet_01v8
spiceprefix=X
}
C {madvlsi/pmos3.sym} 4310 -340 1 0 {name=MP7a
L=2
W=5
body=VDD
nf=1
mult=1
ad="'int((nf+1)/2) * W/nf * 0.29'" 
pd="'2*int((nf+1)/2) * (W/nf + 0.29)'"
as="'int((nf+2)/2) * W/nf * 0.29'" 
ps="'2*int((nf+2)/2) * (W/nf + 0.29)'"
nrd="'0.29 / W'" nrs="'0.29 / W'"
sa=0 sb=0 sd=0
model=pfet_01v8
spiceprefix=X
}
C {madvlsi/nmos3.sym} 1550 -100 3 0 {name=MDUM1
L=2
W=5
body=GND
nf=1
mult=1
ad="'int((nf+1)/2) * W/nf * 0.29'" 
pd="'2*int((nf+1)/2) * (W/nf + 0.29)'"
as="'int((nf+2)/2) * W/nf * 0.29'" 
ps="'2*int((nf+2)/2) * (W/nf + 0.29)'"
nrd="'0.29 / W'" nrs="'0.29 / W'"
sa=0 sb=0 sd=0
model=nfet_01v8
spiceprefix=X
}
C {madvlsi/nmos3.sym} 1650 -100 3 0 {name=MN4a
L=2
W=5
body=GND
nf=1
mult=1
ad="'int((nf+1)/2) * W/nf * 0.29'" 
pd="'2*int((nf+1)/2) * (W/nf + 0.29)'"
as="'int((nf+2)/2) * W/nf * 0.29'" 
ps="'2*int((nf+2)/2) * (W/nf + 0.29)'"
nrd="'0.29 / W'" nrs="'0.29 / W'"
sa=0 sb=0 sd=0
model=nfet_01v8
spiceprefix=X
}
C {madvlsi/nmos3.sym} 1750 -100 3 0 {name=MN4b
L=2
W=5
body=GND
nf=1
mult=1
ad="'int((nf+1)/2) * W/nf * 0.29'" 
pd="'2*int((nf+1)/2) * (W/nf + 0.29)'"
as="'int((nf+2)/2) * W/nf * 0.29'" 
ps="'2*int((nf+2)/2) * (W/nf + 0.29)'"
nrd="'0.29 / W'" nrs="'0.29 / W'"
sa=0 sb=0 sd=0
model=nfet_01v8
spiceprefix=X
}
C {madvlsi/nmos3.sym} 1850 -100 3 0 {name=MN4c
L=2
W=5
body=GND
nf=1
mult=1
ad="'int((nf+1)/2) * W/nf * 0.29'" 
pd="'2*int((nf+1)/2) * (W/nf + 0.29)'"
as="'int((nf+2)/2) * W/nf * 0.29'" 
ps="'2*int((nf+2)/2) * (W/nf + 0.29)'"
nrd="'0.29 / W'" nrs="'0.29 / W'"
sa=0 sb=0 sd=0
model=nfet_01v8
spiceprefix=X
}
C {madvlsi/nmos3.sym} 1950 -100 3 0 {name=MN4d
L=2
W=5
body=GND
nf=1
mult=1
ad="'int((nf+1)/2) * W/nf * 0.29'" 
pd="'2*int((nf+1)/2) * (W/nf + 0.29)'"
as="'int((nf+2)/2) * W/nf * 0.29'" 
ps="'2*int((nf+2)/2) * (W/nf + 0.29)'"
nrd="'0.29 / W'" nrs="'0.29 / W'"
sa=0 sb=0 sd=0
model=nfet_01v8
spiceprefix=X
}
C {madvlsi/nmos3.sym} 2050 -100 3 0 {name=MN4e
L=2
W=5
body=GND
nf=1
mult=1
ad="'int((nf+1)/2) * W/nf * 0.29'" 
pd="'2*int((nf+1)/2) * (W/nf + 0.29)'"
as="'int((nf+2)/2) * W/nf * 0.29'" 
ps="'2*int((nf+2)/2) * (W/nf + 0.29)'"
nrd="'0.29 / W'" nrs="'0.29 / W'"
sa=0 sb=0 sd=0
model=nfet_01v8
spiceprefix=X
}
C {madvlsi/nmos3.sym} 2150 -100 3 0 {name=MN4f
L=2
W=5
body=GND
nf=1
mult=1
ad="'int((nf+1)/2) * W/nf * 0.29'" 
pd="'2*int((nf+1)/2) * (W/nf + 0.29)'"
as="'int((nf+2)/2) * W/nf * 0.29'" 
ps="'2*int((nf+2)/2) * (W/nf + 0.29)'"
nrd="'0.29 / W'" nrs="'0.29 / W'"
sa=0 sb=0 sd=0
model=nfet_01v8
spiceprefix=X
}
C {madvlsi/nmos3.sym} 2450 -100 3 0 {name=MN4i
L=2
W=5
body=GND
nf=1
mult=1
ad="'int((nf+1)/2) * W/nf * 0.29'" 
pd="'2*int((nf+1)/2) * (W/nf + 0.29)'"
as="'int((nf+2)/2) * W/nf * 0.29'" 
ps="'2*int((nf+2)/2) * (W/nf + 0.29)'"
nrd="'0.29 / W'" nrs="'0.29 / W'"
sa=0 sb=0 sd=0
model=nfet_01v8
spiceprefix=X
}
C {madvlsi/nmos3.sym} 2250 -100 3 0 {name=MN4g
L=2
W=5
body=GND
nf=1
mult=1
ad="'int((nf+1)/2) * W/nf * 0.29'" 
pd="'2*int((nf+1)/2) * (W/nf + 0.29)'"
as="'int((nf+2)/2) * W/nf * 0.29'" 
ps="'2*int((nf+2)/2) * (W/nf + 0.29)'"
nrd="'0.29 / W'" nrs="'0.29 / W'"
sa=0 sb=0 sd=0
model=nfet_01v8
spiceprefix=X
}
C {madvlsi/nmos3.sym} 2350 -100 3 0 {name=MN4h
L=2
W=5
body=GND
nf=1
mult=1
ad="'int((nf+1)/2) * W/nf * 0.29'" 
pd="'2*int((nf+1)/2) * (W/nf + 0.29)'"
as="'int((nf+2)/2) * W/nf * 0.29'" 
ps="'2*int((nf+2)/2) * (W/nf + 0.29)'"
nrd="'0.29 / W'" nrs="'0.29 / W'"
sa=0 sb=0 sd=0
model=nfet_01v8
spiceprefix=X
}
C {madvlsi/nmos3.sym} 2550 -100 3 0 {name=MN4j
L=2
W=5
body=GND
nf=1
mult=1
ad="'int((nf+1)/2) * W/nf * 0.29'" 
pd="'2*int((nf+1)/2) * (W/nf + 0.29)'"
as="'int((nf+2)/2) * W/nf * 0.29'" 
ps="'2*int((nf+2)/2) * (W/nf + 0.29)'"
nrd="'0.29 / W'" nrs="'0.29 / W'"
sa=0 sb=0 sd=0
model=nfet_01v8
spiceprefix=X
}
C {madvlsi/nmos3.sym} 2650 -100 3 0 {name=MN4k
L=2
W=5
body=GND
nf=1
mult=1
ad="'int((nf+1)/2) * W/nf * 0.29'" 
pd="'2*int((nf+1)/2) * (W/nf + 0.29)'"
as="'int((nf+2)/2) * W/nf * 0.29'" 
ps="'2*int((nf+2)/2) * (W/nf + 0.29)'"
nrd="'0.29 / W'" nrs="'0.29 / W'"
sa=0 sb=0 sd=0
model=nfet_01v8
spiceprefix=X
}
C {madvlsi/nmos3.sym} 2750 -100 3 0 {name=MN4l
L=2
W=5
body=GND
nf=1
mult=1
ad="'int((nf+1)/2) * W/nf * 0.29'" 
pd="'2*int((nf+1)/2) * (W/nf + 0.29)'"
as="'int((nf+2)/2) * W/nf * 0.29'" 
ps="'2*int((nf+2)/2) * (W/nf + 0.29)'"
nrd="'0.29 / W'" nrs="'0.29 / W'"
sa=0 sb=0 sd=0
model=nfet_01v8
spiceprefix=X
}
C {madvlsi/nmos3.sym} 2850 -100 3 0 {name=MN4m
L=2
W=5
body=GND
nf=1
mult=1
ad="'int((nf+1)/2) * W/nf * 0.29'" 
pd="'2*int((nf+1)/2) * (W/nf + 0.29)'"
as="'int((nf+2)/2) * W/nf * 0.29'" 
ps="'2*int((nf+2)/2) * (W/nf + 0.29)'"
nrd="'0.29 / W'" nrs="'0.29 / W'"
sa=0 sb=0 sd=0
model=nfet_01v8
spiceprefix=X
}
C {madvlsi/nmos3.sym} 3150 -100 3 0 {name=MN4p
L=2
W=5
body=GND
nf=1
mult=1
ad="'int((nf+1)/2) * W/nf * 0.29'" 
pd="'2*int((nf+1)/2) * (W/nf + 0.29)'"
as="'int((nf+2)/2) * W/nf * 0.29'" 
ps="'2*int((nf+2)/2) * (W/nf + 0.29)'"
nrd="'0.29 / W'" nrs="'0.29 / W'"
sa=0 sb=0 sd=0
model=nfet_01v8
spiceprefix=X
}
C {madvlsi/nmos3.sym} 2950 -100 3 0 {name=MN4n
L=2
W=5
body=GND
nf=1
mult=1
ad="'int((nf+1)/2) * W/nf * 0.29'" 
pd="'2*int((nf+1)/2) * (W/nf + 0.29)'"
as="'int((nf+2)/2) * W/nf * 0.29'" 
ps="'2*int((nf+2)/2) * (W/nf + 0.29)'"
nrd="'0.29 / W'" nrs="'0.29 / W'"
sa=0 sb=0 sd=0
model=nfet_01v8
spiceprefix=X
}
C {madvlsi/nmos3.sym} 3050 -100 3 0 {name=MN4o
L=2
W=5
body=GND
nf=1
mult=1
ad="'int((nf+1)/2) * W/nf * 0.29'" 
pd="'2*int((nf+1)/2) * (W/nf + 0.29)'"
as="'int((nf+2)/2) * W/nf * 0.29'" 
ps="'2*int((nf+2)/2) * (W/nf + 0.29)'"
nrd="'0.29 / W'" nrs="'0.29 / W'"
sa=0 sb=0 sd=0
model=nfet_01v8
spiceprefix=X
}
C {madvlsi/nmos3.sym} 3250 -100 3 0 {name=MDUM2
L=2
W=5
body=GND
nf=1
mult=1
ad="'int((nf+1)/2) * W/nf * 0.29'" 
pd="'2*int((nf+1)/2) * (W/nf + 0.29)'"
as="'int((nf+2)/2) * W/nf * 0.29'" 
ps="'2*int((nf+2)/2) * (W/nf + 0.29)'"
nrd="'0.29 / W'" nrs="'0.29 / W'"
sa=0 sb=0 sd=0
model=nfet_01v8
spiceprefix=X
}
C {madvlsi/nmos3.sym} 1250 -100 3 0 {name=MDUM3
L=2
W=5
body=GND
nf=1
mult=1
ad="'int((nf+1)/2) * W/nf * 0.29'" 
pd="'2*int((nf+1)/2) * (W/nf + 0.29)'"
as="'int((nf+2)/2) * W/nf * 0.29'" 
ps="'2*int((nf+2)/2) * (W/nf + 0.29)'"
nrd="'0.29 / W'" nrs="'0.29 / W'"
sa=0 sb=0 sd=0
model=nfet_01v8
spiceprefix=X
}
C {madvlsi/nmos3.sym} 1050 -100 3 0 {name=MDUM4
L=2
W=5
body=GND
nf=1
mult=1
ad="'int((nf+1)/2) * W/nf * 0.29'" 
pd="'2*int((nf+1)/2) * (W/nf + 0.29)'"
as="'int((nf+2)/2) * W/nf * 0.29'" 
ps="'2*int((nf+2)/2) * (W/nf + 0.29)'"
nrd="'0.29 / W'" nrs="'0.29 / W'"
sa=0 sb=0 sd=0
model=nfet_01v8
spiceprefix=X
}
C {madvlsi/nmos3.sym} 750 -100 3 0 {name=MDUM5
L=2
W=5
body=GND
nf=1
mult=1
ad="'int((nf+1)/2) * W/nf * 0.29'" 
pd="'2*int((nf+1)/2) * (W/nf + 0.29)'"
as="'int((nf+2)/2) * W/nf * 0.29'" 
ps="'2*int((nf+2)/2) * (W/nf + 0.29)'"
nrd="'0.29 / W'" nrs="'0.29 / W'"
sa=0 sb=0 sd=0
model=nfet_01v8
spiceprefix=X
}
C {madvlsi/pmos3.sym} 1350 -340 1 0 {name=MDUM6
L=2
W=5
body=VDD
nf=1
mult=1
ad="'int((nf+1)/2) * W/nf * 0.29'" 
pd="'2*int((nf+1)/2) * (W/nf + 0.29)'"
as="'int((nf+2)/2) * W/nf * 0.29'" 
ps="'2*int((nf+2)/2) * (W/nf + 0.29)'"
nrd="'0.29 / W'" nrs="'0.29 / W'"
sa=0 sb=0 sd=0
model=pfet_01v8
spiceprefix=X
}
C {madvlsi/pmos3.sym} 1150 -340 1 0 {name=MDUM7
L=2
W=5
body=VDD
nf=1
mult=1
ad="'int((nf+1)/2) * W/nf * 0.29'" 
pd="'2*int((nf+1)/2) * (W/nf + 0.29)'"
as="'int((nf+2)/2) * W/nf * 0.29'" 
ps="'2*int((nf+2)/2) * (W/nf + 0.29)'"
nrd="'0.29 / W'" nrs="'0.29 / W'"
sa=0 sb=0 sd=0
model=pfet_01v8
spiceprefix=X
}
C {madvlsi/pmos3.sym} 950 -340 1 0 {name=MDUM8
L=2
W=5
body=VDD
nf=1
mult=1
ad="'int((nf+1)/2) * W/nf * 0.29'" 
pd="'2*int((nf+1)/2) * (W/nf + 0.29)'"
as="'int((nf+2)/2) * W/nf * 0.29'" 
ps="'2*int((nf+2)/2) * (W/nf + 0.29)'"
nrd="'0.29 / W'" nrs="'0.29 / W'"
sa=0 sb=0 sd=0
model=pfet_01v8
spiceprefix=X
}
C {madvlsi/pmos3.sym} 750 -340 1 0 {name=MDUM9
L=2
W=5
body=VDD
nf=1
mult=1
ad="'int((nf+1)/2) * W/nf * 0.29'" 
pd="'2*int((nf+1)/2) * (W/nf + 0.29)'"
as="'int((nf+2)/2) * W/nf * 0.29'" 
ps="'2*int((nf+2)/2) * (W/nf + 0.29)'"
nrd="'0.29 / W'" nrs="'0.29 / W'"
sa=0 sb=0 sd=0
model=pfet_01v8
spiceprefix=X
}
C {madvlsi/pmos3.sym} 1550 -340 1 0 {name=MDUM10
L=2
W=5
body=VDD
nf=1
mult=1
ad="'int((nf+1)/2) * W/nf * 0.29'" 
pd="'2*int((nf+1)/2) * (W/nf + 0.29)'"
as="'int((nf+2)/2) * W/nf * 0.29'" 
ps="'2*int((nf+2)/2) * (W/nf + 0.29)'"
nrd="'0.29 / W'" nrs="'0.29 / W'"
sa=0 sb=0 sd=0
model=pfet_01v8
spiceprefix=X
}
C {madvlsi/pmos3.sym} 3250 -340 1 0 {name=MDUM11
L=2
W=5
body=VDD
nf=1
mult=1
ad="'int((nf+1)/2) * W/nf * 0.29'" 
pd="'2*int((nf+1)/2) * (W/nf + 0.29)'"
as="'int((nf+2)/2) * W/nf * 0.29'" 
ps="'2*int((nf+2)/2) * (W/nf + 0.29)'"
nrd="'0.29 / W'" nrs="'0.29 / W'"
sa=0 sb=0 sd=0
model=pfet_01v8
spiceprefix=X
}
C {madvlsi/pmos3.sym} 2350 -340 1 0 {name=MP6a
L=2
W=5
body=VDD
nf=1
mult=1
ad="'int((nf+1)/2) * W/nf * 0.29'" 
pd="'2*int((nf+1)/2) * (W/nf + 0.29)'"
as="'int((nf+2)/2) * W/nf * 0.29'" 
ps="'2*int((nf+2)/2) * (W/nf + 0.29)'"
nrd="'0.29 / W'" nrs="'0.29 / W'"
sa=0 sb=0 sd=0
model=pfet_01v8
spiceprefix=X
}
C {madvlsi/pmos3.sym} 2450 -340 1 0 {name=MP6b
L=2
W=5
body=VDD
nf=1
mult=1
ad="'int((nf+1)/2) * W/nf * 0.29'" 
pd="'2*int((nf+1)/2) * (W/nf + 0.29)'"
as="'int((nf+2)/2) * W/nf * 0.29'" 
ps="'2*int((nf+2)/2) * (W/nf + 0.29)'"
nrd="'0.29 / W'" nrs="'0.29 / W'"
sa=0 sb=0 sd=0
model=pfet_01v8
spiceprefix=X
}
C {madvlsi/pmos3.sym} 3450 -340 1 0 {name=MDUM12
L=2
W=5
body=VDD
nf=1
mult=1
ad="'int((nf+1)/2) * W/nf * 0.29'" 
pd="'2*int((nf+1)/2) * (W/nf + 0.29)'"
as="'int((nf+2)/2) * W/nf * 0.29'" 
ps="'2*int((nf+2)/2) * (W/nf + 0.29)'"
nrd="'0.29 / W'" nrs="'0.29 / W'"
sa=0 sb=0 sd=0
model=pfet_01v8
spiceprefix=X
}
C {madvlsi/pmos3.sym} 3650 -340 1 0 {name=MDUM13
L=2
W=5
body=VDD
nf=1
mult=1
ad="'int((nf+1)/2) * W/nf * 0.29'" 
pd="'2*int((nf+1)/2) * (W/nf + 0.29)'"
as="'int((nf+2)/2) * W/nf * 0.29'" 
ps="'2*int((nf+2)/2) * (W/nf + 0.29)'"
nrd="'0.29 / W'" nrs="'0.29 / W'"
sa=0 sb=0 sd=0
model=pfet_01v8
spiceprefix=X
}
C {madvlsi/pmos3.sym} 3850 -340 1 0 {name=MDUM14
L=2
W=5
body=VDD
nf=1
mult=1
ad="'int((nf+1)/2) * W/nf * 0.29'" 
pd="'2*int((nf+1)/2) * (W/nf + 0.29)'"
as="'int((nf+2)/2) * W/nf * 0.29'" 
ps="'2*int((nf+2)/2) * (W/nf + 0.29)'"
nrd="'0.29 / W'" nrs="'0.29 / W'"
sa=0 sb=0 sd=0
model=pfet_01v8
spiceprefix=X
}
C {madvlsi/pmos3.sym} 4050 -340 1 0 {name=MDUM15
L=2
W=5
body=VDD
nf=1
mult=1
ad="'int((nf+1)/2) * W/nf * 0.29'" 
pd="'2*int((nf+1)/2) * (W/nf + 0.29)'"
as="'int((nf+2)/2) * W/nf * 0.29'" 
ps="'2*int((nf+2)/2) * (W/nf + 0.29)'"
nrd="'0.29 / W'" nrs="'0.29 / W'"
sa=0 sb=0 sd=0
model=pfet_01v8
spiceprefix=X
}
C {madvlsi/nmos3.sym} 3550 -100 3 0 {name=MDUM16
L=2
W=5
body=GND
nf=1
mult=1
ad="'int((nf+1)/2) * W/nf * 0.29'" 
pd="'2*int((nf+1)/2) * (W/nf + 0.29)'"
as="'int((nf+2)/2) * W/nf * 0.29'" 
ps="'2*int((nf+2)/2) * (W/nf + 0.29)'"
nrd="'0.29 / W'" nrs="'0.29 / W'"
sa=0 sb=0 sd=0
model=nfet_01v8
spiceprefix=X
}
C {madvlsi/nmos3.sym} 3750 -100 3 0 {name=MDUM17
L=2
W=5
body=GND
nf=1
mult=1
ad="'int((nf+1)/2) * W/nf * 0.29'" 
pd="'2*int((nf+1)/2) * (W/nf + 0.29)'"
as="'int((nf+2)/2) * W/nf * 0.29'" 
ps="'2*int((nf+2)/2) * (W/nf + 0.29)'"
nrd="'0.29 / W'" nrs="'0.29 / W'"
sa=0 sb=0 sd=0
model=nfet_01v8
spiceprefix=X
}
C {madvlsi/nmos3.sym} 4050 -100 3 0 {name=MDUM18
L=2
W=5
body=GND
nf=1
mult=1
ad="'int((nf+1)/2) * W/nf * 0.29'" 
pd="'2*int((nf+1)/2) * (W/nf + 0.29)'"
as="'int((nf+2)/2) * W/nf * 0.29'" 
ps="'2*int((nf+2)/2) * (W/nf + 0.29)'"
nrd="'0.29 / W'" nrs="'0.29 / W'"
sa=0 sb=0 sd=0
model=nfet_01v8
spiceprefix=X
}
C {madvlsi/pmos3.sym} 4210 -340 1 0 {name=MDUM19
L=2
W=5
body=VDD
nf=1
mult=1
ad="'int((nf+1)/2) * W/nf * 0.29'" 
pd="'2*int((nf+1)/2) * (W/nf + 0.29)'"
as="'int((nf+2)/2) * W/nf * 0.29'" 
ps="'2*int((nf+2)/2) * (W/nf + 0.29)'"
nrd="'0.29 / W'" nrs="'0.29 / W'"
sa=0 sb=0 sd=0
model=pfet_01v8
spiceprefix=X
}
C {madvlsi/pmos4.sym} 4310 -100 3 0 {name=MPGa
L=2
W=5
nf=1
mult=1
ad="'int((nf+1)/2) * W/nf * 0.29'" 
pd="'2*int((nf+1)/2) * (W/nf + 0.29)'"
as="'int((nf+2)/2) * W/nf * 0.29'" 
ps="'2*int((nf+2)/2) * (W/nf + 0.29)'"
nrd="'0.29 / W'" nrs="'0.29 / W'"
sa=0 sb=0 sd=0
model=pfet_01v8
spiceprefix=X
}
C {madvlsi/pmos3.sym} 4410 -340 1 0 {name=MP7b
L=2
W=5
body=VDD
nf=1
mult=1
ad="'int((nf+1)/2) * W/nf * 0.29'" 
pd="'2*int((nf+1)/2) * (W/nf + 0.29)'"
as="'int((nf+2)/2) * W/nf * 0.29'" 
ps="'2*int((nf+2)/2) * (W/nf + 0.29)'"
nrd="'0.29 / W'" nrs="'0.29 / W'"
sa=0 sb=0 sd=0
model=pfet_01v8
spiceprefix=X
}
C {madvlsi/pmos4.sym} 4410 -100 3 0 {name=MPGb
L=2
W=5
nf=1
mult=1
ad="'int((nf+1)/2) * W/nf * 0.29'" 
pd="'2*int((nf+1)/2) * (W/nf + 0.29)'"
as="'int((nf+2)/2) * W/nf * 0.29'" 
ps="'2*int((nf+2)/2) * (W/nf + 0.29)'"
nrd="'0.29 / W'" nrs="'0.29 / W'"
sa=0 sb=0 sd=0
model=pfet_01v8
spiceprefix=X
}
C {madvlsi/pmos3.sym} 4510 -340 1 0 {name=MDUM22
L=2
W=5
body=VDD
nf=1
mult=1
ad="'int((nf+1)/2) * W/nf * 0.29'" 
pd="'2*int((nf+1)/2) * (W/nf + 0.29)'"
as="'int((nf+2)/2) * W/nf * 0.29'" 
ps="'2*int((nf+2)/2) * (W/nf + 0.29)'"
nrd="'0.29 / W'" nrs="'0.29 / W'"
sa=0 sb=0 sd=0
model=pfet_01v8
spiceprefix=X
}
C {madvlsi/pmos4.sym} 4210 -100 3 0 {name=MDUM23
L=2
W=5
nf=1
mult=1
ad="'int((nf+1)/2) * W/nf * 0.29'" 
pd="'2*int((nf+1)/2) * (W/nf + 0.29)'"
as="'int((nf+2)/2) * W/nf * 0.29'" 
ps="'2*int((nf+2)/2) * (W/nf + 0.29)'"
nrd="'0.29 / W'" nrs="'0.29 / W'"
sa=0 sb=0 sd=0
model=pfet_01v8
spiceprefix=X
}
C {madvlsi/pmos4.sym} 4510 -100 3 0 {name=MDUM24
L=2
W=5
nf=1
mult=1
ad="'int((nf+1)/2) * W/nf * 0.29'" 
pd="'2*int((nf+1)/2) * (W/nf + 0.29)'"
as="'int((nf+2)/2) * W/nf * 0.29'" 
ps="'2*int((nf+2)/2) * (W/nf + 0.29)'"
nrd="'0.29 / W'" nrs="'0.29 / W'"
sa=0 sb=0 sd=0
model=pfet_01v8
spiceprefix=X
}
